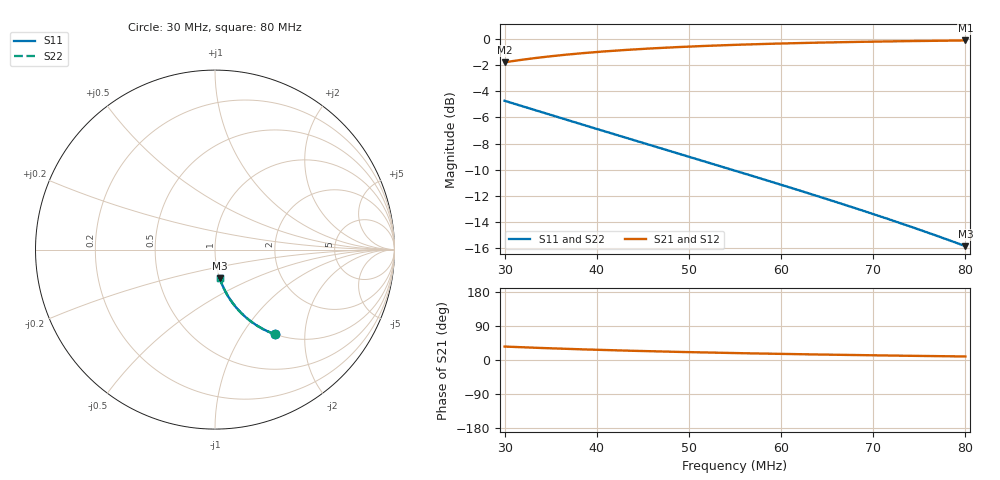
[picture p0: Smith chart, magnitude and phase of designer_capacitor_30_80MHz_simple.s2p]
! Touchstone file exported from Circuit Design 2018.2.0
!  File:  C:/Users/JH218595/Documents/scikit-rf/doc/source/examples/circuit/examples_circuits.aedt
!  Generated:  9:45:07  avr. 28, 2019
!  Design:  capacitor_eqmodel_simple
!  Project:  examples_circuits
!  Setup:  LinearFrequency
!  Solution:  LinearFrequency
! Variables:
!  C = 70pF
# GHZ S MA R 50.000000
! Modal data exported
! Port[1] = Port1
! Port[2] = Port2
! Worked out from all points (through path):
!   501 points, 30 MHz to 80 MHz, reference 50 ohm
!   highest |S21| = -0.11 dB at 80 MHz (marker M1); lowest = -1.8 dB at 30 MHz (marker M2)
!   lowest |S11| = -15.8 dB at 80 MHz (marker M3), VSWR 1.38, Z = 50 - j16.4 ohm
!   |S11| at or under -10 dB: 54.68 MHz to end of sweep
!   |S22| runs from -15.8 to -4.7 dB; largest |S21 - S12| = 1.8e-15
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0.03  0.5804 -54.5  0.8144 35.5  0.8144 35.5  0.5804 -54.5
! Port Impedance50 0 50 0
0.0302  0.5775 -54.7  0.8164 35.3  0.8164 35.3  0.5775 -54.7
0.0313  0.5619 -55.8  0.8272 34.2  0.8272 34.2  0.5619 -55.8
0.0324  0.5467 -56.9  0.8373 33.1  0.8373 33.1  0.5467 -56.9
0.0342  0.5228 -58.5  0.8525 31.5  0.8525 31.5  0.5228 -58.5
0.0363  0.4963 -60.2  0.8682 29.8  0.8682 29.8  0.4963 -60.2
0.0384  0.4712 -61.9  0.882 28.1  0.882 28.1  0.4712 -61.9
0.0404  0.4485 -63.3  0.8938 26.7  0.8938 26.7  0.4485 -63.3
0.0424  0.4271 -64.7  0.9042 25.3  0.9042 25.3  0.4271 -64.7
0.0445  0.4057 -66.1  0.914 23.9  0.914 23.9  0.4057 -66.1
0.0467  0.3844 -67.4  0.9232 22.6  0.9232 22.6  0.3844 -67.4
0.0487  0.3661 -68.5  0.9306 21.5  0.9306 21.5  0.3661 -68.5
0.0507  0.3487 -69.6  0.9373 20.4  0.9373 20.4  0.3487 -69.6
0.0528  0.3312 -70.7  0.9436 19.3  0.9436 19.3  0.3312 -70.7
0.055  0.3138 -71.7  0.9495 18.3  0.9495 18.3  0.3138 -71.7
0.0591  0.2835 -73.5  0.959 16.5  0.959 16.5  0.2835 -73.5
0.0634  0.2544 -75.3  0.9671 14.7  0.9671 14.7  0.2544 -75.3
0.0674  0.2294 -76.7  0.9733 13.3  0.9733 13.3  0.2294 -76.7
0.0717  0.2046 -78.2  0.9789 11.8  0.9789 11.8  0.2046 -78.2
0.0754  0.1846 -79.4  0.9828 10.6  0.9828 10.6  0.1846 -79.4
0.0798  0.1624 -80.7  0.9867 9.3  0.9867 9.3  0.1624 -80.7
0.08  0.1614 -80.7  0.9869 9.3  0.9869 9.3  0.1614 -80.7
